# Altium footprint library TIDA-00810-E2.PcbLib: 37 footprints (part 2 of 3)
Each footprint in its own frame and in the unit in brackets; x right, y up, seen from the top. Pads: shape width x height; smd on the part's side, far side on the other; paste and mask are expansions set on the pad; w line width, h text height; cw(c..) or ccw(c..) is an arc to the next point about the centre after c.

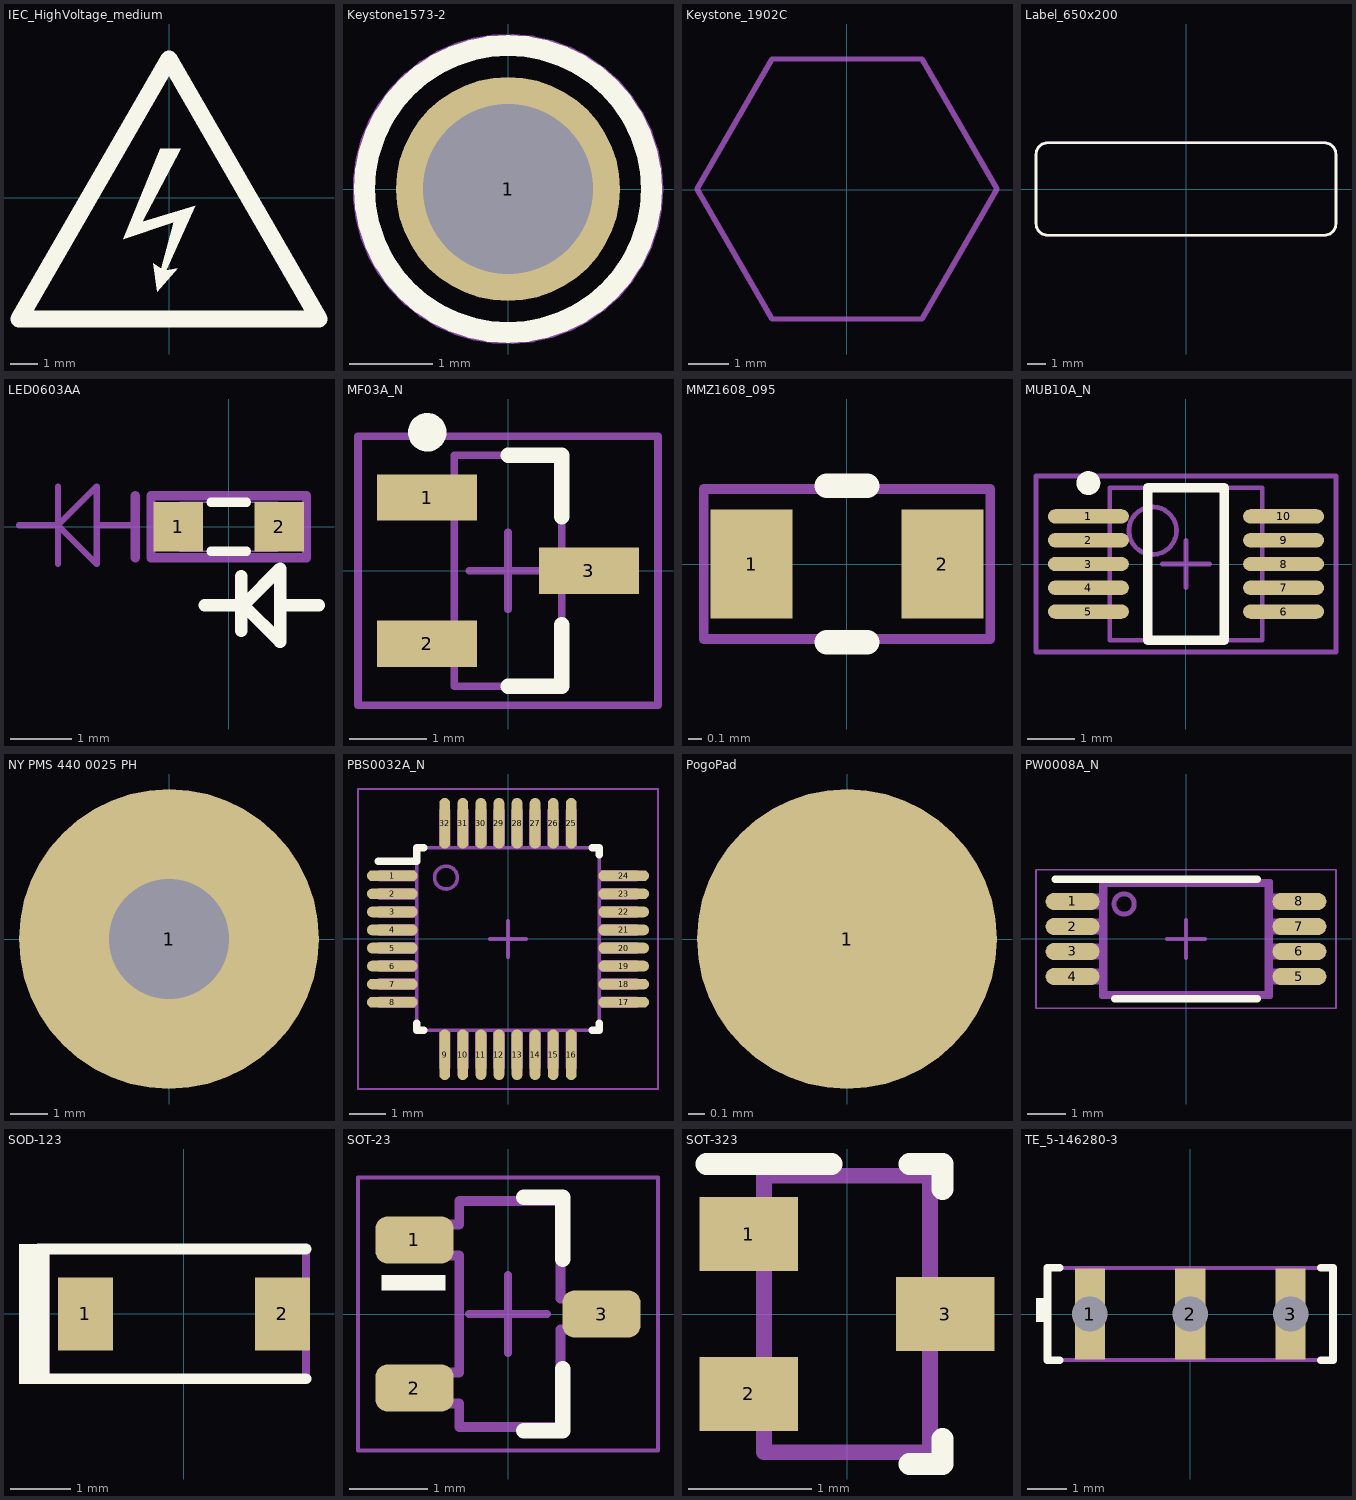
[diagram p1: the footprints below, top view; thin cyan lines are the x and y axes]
## IEC_HighVoltage_medium [mm]
Top Overlay:
  region: -0.33,1.803 0.432,1.803 -0.991,-0.889 0.965,-0.305 -0.102,-2.667 0.33,-2.591 -0.432,-3.454 -0.584,-2.413 -0.279,-2.616 0.178,-0.914 -1.676,-1.524
  lines w0.635: -5.512,-4.458 0,5.089 5.512,-4.458 -5.512,-4.458

## Keystone1573-2 [mm] "Double Turret"
height 4.7
pads (1):
  round 2.7 hole 2.05: 1(0,0)
Top Overlay:
  circle w0.254: c0,0 r1.727
Mechanical 5:
  circle w0.127: c0,0 r1.805
  text ".Designator" at -1.397,-0.381 h0.76
3D body "Keystone1573-2.stp": height 4.72, standoff -2.06, extent -1.18,-1.178 1.171,1.178

## Keystone_1902C [mil] "Hex Standoff, 4-40 threaded, nylon"
height 500
pads (1):
  round 1 on Mech3: 0(0,0)
Mechanical 5:
  lines w5: -145.29,0.49 -72.56,126.47 72.92,126.47 145.65,0.49 72.92,-125.49 -72.56,-125.49 -145.29,0.49
  text ".Designator" at -60,-20 h25
3D body "Keystone_1902C.stp": height 501, standoff 1, extent -144.95,-125.98 146,125.98

## Label_650x200 [mil] "Thermal Transfer Label"
height 1
pads (1):
  round 1 on Mech13: 0(0,0)
Top Overlay:
  lines w6: -325,-75 ccw(c-300,-75) -300,-100 300,-100 ccw(c300,-75) 325,-75 325,75 ccw(c300,75) 300,100 -300,100 ccw(c-300,75) -325,75 -325,-75
Mechanical 5:
  lines w5: -325,-75 ccw(c-300,-75) -300,-100 300,-100 ccw(c300,-75) 325,-75 325,75 ccw(c300,75) 300,100 -300,100 ccw(c-300,75) -325,75 -325,-75
  text ".Designator" at -60,-20 h25
3D body: height 1, standoff 0, extent -325.02,-100.02 325.02,100.02

## LED0603AA [mil]
height 118.11
pads (2):
  rect 32x32 smd: 1(-32.48,0) 2(32.48,0)
Top Overlay:
  lines w6: -11.42,-15.75 11.42,-15.75 ; -11.42,15.75 11.42,15.75
  lines w8: -15.58,-50.44 9.42,-50.44 33,-26.85 33,-73.81 ; 8,-66.85 8,-31.85 ; 9.62,-50.44 33,-73.81 ; 32.79,-73.81 33,-73.81 ; 33,-50.33 58,-50.33
Mechanical 5:
  lines w6: -60,-20 -60,20 ; -50,-20 -50,20 50,20 50,-20 -50,-20
  text ".designator" at -140,-10 h25
Mechanical 15:
  lines w1: -31.5,-15.75 -31.5,15.75 31.5,15.75 31.5,-15.75 -31.5,-15.75
  lines w3.94: -134.79,0.96 -109.79,0.96 ; -109.79,-24.04 -109.79,25.96 ; -84.79,0.96 -59.79,0.96 ; -109.79,0.96 -84.79,-24.04 -84.79,25.96 -109.79,0.96

## MF03A_N [mm] "SOT23, 3-Leads, Body 2.9x1.3mm, Pitch 0.95mm, Lead Span 2.4mm, IPC Medium Density"
height 1.12
pads (3):
  rect 1.3x0.6 smd: 1(-1.05,0.95) 2(-1.05,-0.95) 3(1.05,0)
Top Overlay:
  circle w0.25: c-1.05,1.8 r0.125
  lines w0.2: 0,-1.5 0.7,-1.5 0.7,-0.7 ; 0,1.5 0.7,1.5 0.7,0.7
Mechanical 5:
  text ".Designator" at -0.254,-0.762 h0.64
Mechanical 13:
  lines w0.1: -0.7,-1.5 0.7,-1.5 0.7,1.5 -0.7,1.5 -0.7,-1.5
Mechanical 15:
  lines w0.1: -0.5,0 0.5,0 ; 0,-0.5 0,0.5 ; -1.95,-1.75 1.95,-1.75 1.95,1.75 -1.95,1.75 -1.95,-1.75
3D body: height 1.12, standoff 0, extent -0.7,-1.5 0.7,1.5

## MMZ1608_095 [mm] "TDK"
height 0.95
pads (2):
  rect 0.6x0.8 smd: 1(-0.7,0) 2(0.7,0)
Top Overlay:
  lines w0.18: -0.15,-0.575 0.15,-0.575 ; -0.15,0.575 0.15,0.575
Mechanical 5:
  lines w0.07: -1.05,-0.55 -1.05,0.55 1.05,0.55 1.05,-0.55 -1.05,-0.55
  text ".Designator" at -0.508,-0.356 h0.64
3D body: height 0.95, standoff 0, extent -0.874,-0.474 -0.501,0.474
3D body: height 0.95, standoff 0, extent -0.499,-0.474 0.499,0.474
3D body: height 0.95, standoff 0, extent 0.501,-0.474 0.874,0.474

## MUB10A_N [mm] "TSSOP, 10-Leads, Body 3x3mm, Pitch 0.5mm, IPC Medium Density"
height 1.09
pads (10):
  oval 1.7x0.3 smd: 1(-2.05,1) 2(-2.05,0.5) 3(-2.05,0) 4(-2.05,-0.5) 5(-2.05,-1) 6(2.05,-1) 7(2.05,-0.5) 8(2.05,0) 9(2.05,0.5) 10(2.05,1)
Top Overlay:
  circle w0.25: c-2.05,1.7 r0.125
  lines w0.2: -0.8,-1.6 0.8,-1.6 0.8,1.6 -0.8,1.6 -0.8,-1.6
Mechanical 5:
  text ".Designator" at -0.379,0.508 h0.64
Mechanical 13:
  circle w0.1: c-0.7,0.7 r0.5
  lines w0.1: -1.6,-1.6 1.6,-1.6 1.6,1.6 -1.6,1.6 -1.6,-1.6
Mechanical 15:
  lines w0.1: -0.5,0 0.5,0 ; 0,-0.5 0,0.5 ; -3.15,-1.85 3.15,-1.85 3.15,1.85 -3.15,1.85 -3.15,-1.85
3D body: height 1.09, standoff 0, extent -1.6,-1.6 1.6,1.6

## NY PMS 440 0025 PH [mm] "4-40 nylon screw and mounting hole"
height 1.905
pads (1):
  round 8 hole 3.2: 1(0,0)
Mechanical 5:
  circle w0.127: c0,0 r3.789
  text ".Designator" at -0.446,-0.131 h0.64
3D body "B_F_NY PMS 440 0025 PH.stp": height 2.69, standoff -8.74, extent -3.302,-3.3 3.296,3.3

## PBS0032A_N [mm]
height 1.2
pads (32):
  oval 1.4x0.3 smd: 1(-3.2,1.75) 2(-3.2,1.25) 3(-3.2,0.75) 4(-3.2,0.25) 5(-3.2,-0.25) 6(-3.2,-0.75) 7(-3.2,-1.25) 8(-3.2,-1.75) 17(3.2,-1.75) 18(3.2,-1.25) 19(3.2,-0.75) 20(3.2,-0.25) 21(3.2,0.25) 22(3.2,0.75) 23(3.2,1.25) 24(3.2,1.75)
  oval 0.3x1.4 smd: 9(-1.75,-3.2) 10(-1.25,-3.2) 11(-0.75,-3.2) 12(-0.25,-3.2) 13(0.25,-3.2) 14(0.75,-3.2) 15(1.25,-3.2) 16(1.75,-3.2) 25(1.75,3.2) 26(1.25,3.2) 27(0.75,3.2) 28(0.25,3.2) 29(-0.25,3.2) 30(-0.75,3.2) 31(-1.25,3.2) 32(-1.75,3.2)
Top Overlay:
  lines w0.2: -3.6,2.15 -2.527,2.15 -2.527,2.527 -2.327,2.527 ; -2.527,-2.327 -2.527,-2.527 -2.327,-2.527 ; 2.327,-2.527 2.527,-2.527 2.527,-2.327 ; 2.327,2.527 2.527,2.527 2.527,2.327
Mechanical 5:
  circle w0.1: c-1.716,1.7 r0.316
  lines w0.1: -3.556,-1.864 -2.527,-1.864 -2.527,-1.636 -3.556,-1.636 -3.556,-1.864 ; -3.556,-1.364 -2.527,-1.364 -2.527,-1.136 -3.556,-1.136 -3.556,-1.364 ; -3.556,-0.864 -2.527,-0.864 -2.527,-0.636 -3.556,-0.636 -3.556,-0.864 ; -3.556,-0.364 -2.527,-0.364 -2.527,-0.136 -3.556,-0.136 -3.556,-0.364 ; -3.556,0.136 -2.527,0.136 -2.527,0.364 -3.556,0.364 -3.556,0.136 ; -3.556,0.636 -2.527,0.636 -2.527,0.864 -3.556,0.864 -3.556,0.636 ; -3.556,1.136 -2.527,1.136 -2.527,1.364 -3.556,1.364 -3.556,1.136 ; -3.556,1.636 -2.527,1.636 -2.527,1.864 -3.556,1.864 -3.556,1.636 ; -2.527,-2.527 -2.527,2.527 2.527,2.527 2.527,-2.527 -2.527,-2.527 ; -1.864,-3.556 -1.636,-3.556 -1.636,-2.527 -1.864,-2.527 -1.864,-3.556 ; -1.864,2.527 -1.864,3.556 -1.636,3.556 -1.636,2.527 -1.864,2.527 ; -1.364,-3.556 -1.136,-3.556 -1.136,-2.527 -1.364,-2.527 -1.364,-3.556 ; -1.364,2.527 -1.364,3.556 -1.136,3.556 -1.136,2.527 -1.364,2.527 ; -0.864,-3.556 -0.636,-3.556 -0.636,-2.527 -0.864,-2.527 -0.864,-3.556 ; -0.864,2.527 -0.864,3.556 -0.636,3.556 -0.636,2.527 -0.864,2.527 ; -0.364,-3.556 -0.136,-3.556 -0.136,-2.527 -0.364,-2.527 -0.364,-3.556 ; -0.364,2.527 -0.364,3.556 -0.136,3.556 -0.136,2.527 -0.364,2.527 ; 0.136,-3.556 0.364,-3.556 0.364,-2.527 0.136,-2.527 0.136,-3.556 ; 0.136,2.527 0.136,3.556 0.364,3.556 0.364,2.527 0.136,2.527 ; 0.636,-3.556 0.864,-3.556 0.864,-2.527 0.636,-2.527 0.636,-3.556 ; 0.636,2.527 0.636,3.556 0.864,3.556 0.864,2.527 0.636,2.527 ; 1.136,-3.556 1.364,-3.556 1.364,-2.527 1.136,-2.527 1.136,-3.556 ; 1.136,2.527 1.136,3.556 1.364,3.556 1.364,2.527 1.136,2.527 ; 1.636,-3.556 1.864,-3.556 1.864,-2.527 1.636,-2.527 1.636,-3.556 ; 1.636,2.527 1.636,3.556 1.864,3.556 1.864,2.527 1.636,2.527 ; 2.527,-1.864 3.556,-1.864 3.556,-1.636 2.527,-1.636 2.527,-1.864 ; 2.527,-1.364 3.556,-1.364 3.556,-1.136 2.527,-1.136 2.527,-1.364 ; 2.527,-0.864 3.556,-0.864 3.556,-0.636 2.527,-0.636 2.527,-0.864 ; 2.527,-0.364 3.556,-0.364 3.556,-0.136 2.527,-0.136 2.527,-0.364 ; 2.527,0.136 3.556,0.136 3.556,0.364 2.527,0.364 2.527,0.136 ; 2.527,0.636 3.556,0.636 3.556,0.864 2.527,0.864 2.527,0.636 ; 2.527,1.136 3.556,1.136 3.556,1.364 2.527,1.364 2.527,1.136 ; 2.527,1.636 3.556,1.636 3.556,1.864 2.527,1.864 2.527,1.636
  text ".Designator" at 0.364,-0.51 h0.64
Mechanical 15:
  lines w0.05: -4.15,-4.15 -4.15,4.15 4.15,4.15 4.15,-4.15 -4.15,-4.15
  lines w0.1: -0.5,0 0.5,0 ; 0,-0.5 0,0.5
3D body "PBS0032A.stp": height 1.2, standoff 0, extent -3.505,-3.505 3.506,3.506

## PogoPad [mil] "No Solder Paste"
pads (1):
  round 70 smd paste-35: 1(0,0)

## PW0008A_N [mm] "TSOP, 8-Leads, Body 3x4.4mm, Pitch 0.65mm, IPC Medium Density"
height 1.2
pads (8):
  oval 1.4x0.45 smd: 1(-2.95,0.975) 2(-2.95,0.325) 3(-2.95,-0.325) 4(-2.95,-0.975) 5(2.95,-0.975) 6(2.95,-0.325) 7(2.95,0.325) 8(2.95,0.975)
Top Overlay:
  lines w0.2: -3.4,1.55 1.85,1.55 ; -1.85,-1.55 1.85,-1.55
Mechanical 5:
  lines w0.127: -2.2,-1.5 -2.2,-1.125 ; -2.2,-1.5 2.2,-1.5 ; -2.2,-1.5 -2.11,-1.41 ; -2.2,-1.125 -2.4,-1.125 -2.669,-1.125 -2.785,-1.125 -2.856,-1.125 -3.228,-1.125 -3.228,-0.825 -2.856,-0.825 -2.785,-0.825 -2.669,-0.825 -2.4,-0.825 -2.2,-0.825 ; -2.2,-1.125 -2.2,-0.825 ; -2.2,-0.825 -2.2,-0.475 ; -2.2,-0.475 -2.2,-0.175 ; -2.2,-0.475 -2.4,-0.475 -2.669,-0.475 -2.785,-0.475 -2.856,-0.475 -3.228,-0.475 -3.228,-0.175 -2.856,-0.175 -2.785,-0.175 -2.669,-0.175 -2.4,-0.175 -2.2,-0.175 ; -2.2,-0.175 -2.2,0.175 ; -2.2,0.175 -2.4,0.175 -2.669,0.175 -2.785,0.175 -2.856,0.175 -3.228,0.175 -3.228,0.475 -2.856,0.475 -2.785,0.475 -2.669,0.475 -2.4,0.475 -2.2,0.475 ; -2.2,0.175 -2.2,0.475 ; -2.2,0.475 -2.2,0.825 ; -2.2,0.825 -2.2,1.125 ; -2.2,0.825 -2.4,0.825 -2.669,0.825 -2.785,0.825 -2.856,0.825 -3.228,0.825 -3.228,1.125 -2.856,1.125 -2.785,1.125 -2.669,1.125 -2.4,1.125 -2.2,1.125 ; -2.2,1.125 -2.2,1.5 ; -2.2,1.5 2.2,1.5 ; -2.2,1.5 -2.11,1.41 ; -2.11,-1.41 2.11,-1.41 ; -2.11,-1.41 -2.11,1.41 ; -2.11,1.41 2.11,1.41 ; 2.11,-1.41 2.2,-1.5 ; 2.11,-1.41 2.11,1.41 ; 2.11,1.41 2.2,1.5 ; 2.2,-1.5 2.2,-1.125 ; 2.2,-1.125 2.4,-1.125 2.669,-1.125 2.785,-1.125 2.856,-1.125 3.228,-1.125 3.228,-0.825 2.856,-0.825 2.785,-0.825 2.669,-0.825 2.4,-0.825 2.2,-0.825 ; 2.2,-1.125 2.2,-0.825 ; 2.2,-0.825 2.2,-0.475 ; 2.2,-0.475 2.4,-0.475 2.669,-0.475 2.785,-0.475 2.856,-0.475 3.228,-0.475 3.228,-0.175 2.856,-0.175 2.785,-0.175 2.669,-0.175 2.4,-0.175 2.2,-0.175 ; 2.2,-0.475 2.2,-0.175 ; 2.2,-0.175 2.2,0.175 ; 2.2,0.175 2.2,0.475 ; 2.2,0.175 2.4,0.175 2.669,0.175 2.785,0.175 2.856,0.175 3.228,0.175 3.228,0.475 2.856,0.475 2.785,0.475 2.669,0.475 2.4,0.475 2.2,0.475 ; 2.2,0.475 2.2,0.825 ; 2.2,0.825 2.2,1.125 ; 2.2,0.825 2.4,0.825 2.669,0.825 2.785,0.825 2.856,0.825 3.228,0.825 3.228,1.125 2.856,1.125 2.785,1.125 2.669,1.125 2.4,1.125 2.2,1.125 ; 2.2,1.125 2.2,1.5 ; -1.61,0.646 ccw(c-1.61,0.91) -1.61,1.173 ccw(c-1.61,0.91) -1.61,0.646
  text ".Designator" at 0.635,0.254 h0.64
Mechanical 15:
  lines w0.05: -3.9,-1.8 3.9,-1.8 3.9,1.8 -3.9,1.8 -3.9,-1.8
  lines w0.1: -0.5,0 0.5,0 ; 0,-0.5 0,0.5
3D body "PW0008A.stp": height 1.2, standoff 0, extent -3.208,-1.5 3.208,1.5

## SOD-123 [mm] "On Semi recommended land pattern"
height 1.35
pads (2):
  rect 0.915x1.22 smd: 1(-1.637,0) 2(1.637,0)
Top Overlay:
  rectangle: -2.743,-1.169 -2.235,1.168
  lines w0.178: -2.413,-1.079 2.032,-1.079 ; -2.413,1.079 2.032,1.079
Mechanical 5:
  rectangle: -2.743,-1.169 -2.235,1.168
  lines w0.127: -2.413,-1.079 2.032,-1.079 2.032,1.079 -2.413,1.079
  text ".Designator" at 0.381,0.381 h0.64
3D body "SOD-123.stp": height 1.35, standoff 0, extent -1.932,-0.9 1.932,0.9

## SOT-23 [mm] "SOT23, 3-Leads, Body 2.9x1.3mm, Pitch 0.95mm, Lead Span 2.5mm, IPC Medium Density"
height 1.1
pads (3):
  rrect50% 1x0.6 smd: 1(-1.2,0.95) 2(-1.2,-0.95) 3(1.2,0)
Top Overlay:
  rectangle: -1.625,0.3 -0.8,0.5
  lines w0.2: 0.2,-1.5 0.7,-1.5 0.7,-0.7 ; 0.2,1.5 0.7,1.5 0.7,0.7
Mechanical 5:
  lines w0.127: -1.16,-1.15 -1.16,-0.75 -0.625,-0.75 -0.625,0.75 -1.16,0.75 -1.16,1.15 -0.625,1.15 -0.625,1.45 0.675,1.45 0.675,0.2 1.21,0.2 1.21,-0.2 0.675,-0.2 0.675,-1.45 -0.625,-1.45 -0.625,-1.15 -1.16,-1.15
  text ".Designator" at 0.305,-0.762 h0.64
Mechanical 15:
  lines w0.05: -1.925,-1.75 1.925,-1.75 1.925,1.75 -1.925,1.75 -1.925,-1.75
  lines w0.1: -0.5,0 0.5,0 ; 0,-0.5 0,0.5
3D body "SW3dPS-sot-3p290x130ll237h100.STEP": height 1, standoff 0, extent -1.16,-1.45 1.21,1.45

## SOT-323 [mm] "Zetex recommended land pattern.  March 2007"
height 1.1
pads (3):
  rect 0.8x0.6 smd: 1(-0.8,0.65) 2(-0.8,-0.65) 3(0.8,0)
Top Overlay:
  lines w0.178: -1.143,1.219 -0.127,1.219 ; 0.508,-1.219 0.775,-1.219 0.775,-1.016 ; 0.508,1.219 0.775,1.219 0.775,1.016
Mechanical 5:
  lines w0.127: -1.125,-0.8 -1.125,-0.5 -0.975,-0.5 -0.935,-0.5 -0.884,-0.5 -0.725,-0.5 -0.675,-0.5 -0.675,-0.8 -0.725,-0.8 -0.884,-0.8 -0.935,-0.8 -0.975,-0.8 -1.125,-0.8 ; -1.125,0.5 -1.125,0.8 -0.975,0.8 -0.935,0.8 -0.884,0.8 -0.725,0.8 -0.675,0.8 -0.675,0.5 -0.725,0.5 -0.884,0.5 -0.935,0.5 -0.975,0.5 -1.125,0.5 ; -0.675,-1.125 -0.675,1.125 0.675,1.125 0.675,-1.125 -0.675,-1.125 ; 0.675,-0.15 0.725,-0.15 0.884,-0.15 0.935,-0.15 0.975,-0.15 1.125,-0.15 1.125,0.15 0.975,0.15 0.935,0.15 0.884,0.15 0.725,0.15 0.675,0.15 0.675,-0.15
  text ".Designator" at 0.254,-0.508 h0.64
3D body "SC-70.stp": height 1.13, standoff 0.02, extent -1.125,-1.125 1.125,1.125

## TE_5-146280-3 [mm] "Header, 2.54mm, 3x1, TH"
height 8.72
pads (3):
  rect 0.76x2.29 hole 0.89: 1(-2.54,0) 2(0,0) 3(2.54,0)
Top Overlay:
  rectangle: -3.9,-0.2 -3.6,0.4
  lines w0.2: -3.3,-1.168 -3.607,-1.168 -3.607,1.169 -3.3,1.169 ; 3.3,-1.168 3.607,-1.168 3.607,1.169 3.3,1.169
Mechanical 5:
  lines w0.1: -3.607,-1.168 -3.607,1.169 3.607,1.169 3.607,-1.168 -3.607,-1.168 ; -2.851,-0.311 -2.851,0.311 -2.229,0.311 -2.229,-0.311 -2.851,-0.311
  text ".Designator" at -0.762,-0.254 h0.64
3D body "c-5-146280-3-g-3d.stp": height 8.13, standoff -3.05, extent -3.607,-1.168 3.607,1.169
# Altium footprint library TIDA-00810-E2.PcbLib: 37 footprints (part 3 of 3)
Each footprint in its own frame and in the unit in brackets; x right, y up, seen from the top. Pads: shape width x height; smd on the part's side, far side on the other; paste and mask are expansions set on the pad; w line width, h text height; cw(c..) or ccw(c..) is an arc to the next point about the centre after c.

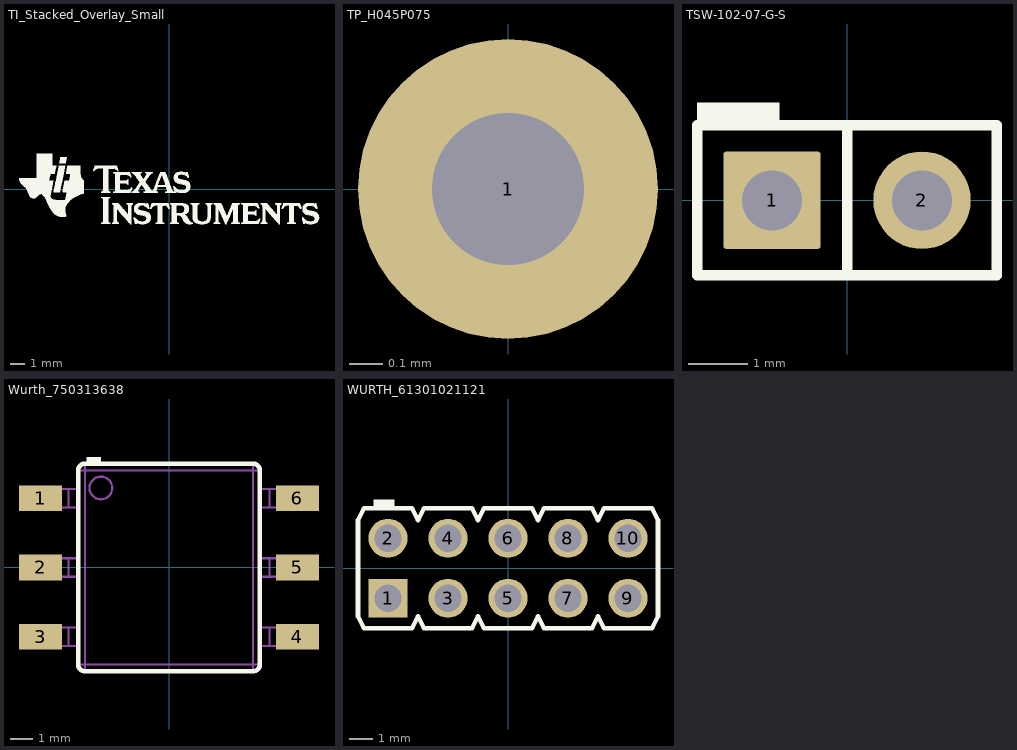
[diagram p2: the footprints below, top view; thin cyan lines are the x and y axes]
## TI_Stacked_Overlay_Small [mm]
Top Overlay:
  drawing of 18 lines, arcs and shapes, not listed

## TP_H045P075 [mil] "TP_H0.45P0.75"
height 104.33
pads (1):
  round 35 hole 17.72: 1(0,0)

## TSW-102-07-G-S [mm] "Samtec 100mil, 1x2, 230 mil above insulator"
height 8.382
pads (2):
  rrect6% 1.65x1.65 hole 1.016: 1(-1.27,0)
  round 1.65 hole 1.016: 2(1.27,0)
Top Overlay:
  rectangle: -2.54,1.27 -1.143,1.651
  lines w0.178: 0,-1.27 0,1.27 ; -2.54,-1.27 2.54,-1.27 2.54,1.27 -2.54,1.27 -2.54,-1.27
Mechanical 5:
  lines w0.127: -2.54,-1.27 -2.54,1.27 2.54,1.27 2.54,-1.27 -2.54,-1.27
  text ".Designator" at 0.762,0.254 h0.64
3D body "SamtecTSW-07_2x1.stp": height 8.38, standoff -2.54, extent -2.54,-1.27 2.54,1.27

## Wurth_750313638 [mm] "SMD, 6-Leads, Body 8x9.14mm, Pitch 3.05mm"
height 7.62
pads (6):
  rect 1.9x1.14 smd: 1(-5.655,3.05) 2(-5.655,0) 3(-5.655,-3.05) 4(5.655,-3.05) 5(5.655,0) 6(5.655,3.05)
Top Overlay:
  rectangle: -3.625,4.57 -3,4.875
  lines w0.2: -4,-4.27 ccw(c-3.7,-4.27) -3.7,-4.57 3.7,-4.57 ccw(c3.7,-4.27) 4,-4.27 4,4.27 ccw(c3.7,4.27) 3.7,4.57 -3.7,4.57 ccw(c-3.7,4.27) -4,4.27 -4,-4.27
Mechanical 5:
  circle w0.1: c-3,3.5 r0.5
  lines w0.1: -4,-3.455 -4.43,-3.455 ; -4,-2.645 -4.43,-2.645 ; -4,-0.405 -4.43,-0.405 ; -4,0.405 -4.43,0.405 ; -4,2.645 -4.43,2.645 ; -4,3.455 -4.43,3.455 ; 4,-3.455 4.43,-3.455 ; 4,-2.645 4.43,-2.645 ; 4,-0.405 4.43,-0.405 ; 4,0.405 4.43,0.405 ; 4,2.645 4.43,2.645 ; 4,3.455 4.43,3.455 ; -5.47,-3.455 -5.376,-3.455 ; -5.47,-3.455 -6.35,-3.455 -6.35,-2.645 -5.47,-2.645 ; -5.47,-3.455 -5.47,-2.645 ; -5.47,-2.645 -5.376,-2.645 ; -5.47,-0.405 -6.35,-0.405 -6.35,0.405 -5.47,0.405 ; -5.47,-0.405 -5.376,-0.405 ; -5.47,-0.405 -5.47,0.405 ; -5.47,0.405 -5.376,0.405 ; -5.47,2.645 -5.376,2.645 ; -5.47,2.645 -6.35,2.645 -6.35,3.455 -5.47,3.455 ; -5.47,2.645 -5.47,3.455 ; -5.47,3.455 -5.376,3.455 ; -5.376,-3.455 -4.9,-3.455 ; -5.376,-3.455 -5.376,-2.645 ; -5.376,-2.645 -4.9,-2.645 ; -5.376,-0.405 -4.9,-0.405 ; -5.376,-0.405 -5.376,0.405 ; -5.376,0.405 -4.9,0.405 ; -5.376,2.645 -4.9,2.645 ; -5.376,2.645 -5.376,3.455 ; -5.376,3.455 -4.9,3.455 ; -4.9,-3.455 -4.43,-3.455 ; -4.9,-3.455 -4.9,-2.645 ; -4.9,-2.645 -4.43,-2.645 ; -4.9,-0.405 -4.43,-0.405 ; -4.9,-0.405 -4.9,0.405 ; -4.9,0.405 -4.43,0.405 ; -4.9,2.645 -4.43,2.645 ; -4.9,2.645 -4.9,3.455 ; -4.9,3.455 -4.43,3.455 ; -4.43,-3.455 -4.43,-2.645 ; -4.43,-0.405 -4.43,0.405 ; -4.43,2.645 -4.43,3.455 ; -4,-4.27 ccw(c-3.7,-4.27) -3.7,-4.57 ; -4,-4.27 -4,4.27 ; -4,-4.27 -3.7,-4.27 ; -4,4.27 cw(c-3.7,4.27) -3.7,4.57 ; -4,4.27 -3.7,4.27 ; -3.7,-4.57 3.7,-4.57 ; -3.7,-4.57 -3.7,-4.27 ; -3.7,-4.27 -3.7,4.27 ; -3.7,-4.27 3.7,-4.27 ; -3.7,4.27 3.7,4.27 ; -3.7,4.27 -3.7,4.57 ; -3.7,4.57 3.7,4.57 ; 3.7,-4.57 ccw(c3.7,-4.27) 4,-4.27 ; 3.7,-4.57 3.7,-4.27 ; 3.7,-4.27 3.7,4.27 ; 3.7,-4.27 4,-4.27 ; 3.7,4.27 3.7,4.57 ; 3.7,4.27 4,4.27 ; 3.7,4.57 cw(c3.7,4.27) 4,4.27 ; 4,-4.27 4,4.27 ; 4.43,-3.455 4.9,-3.455 ; 4.43,-3.455 4.43,-2.645 ; 4.43,-2.645 4.9,-2.645 ; 4.43,-0.405 4.9,-0.405 ; 4.43,-0.405 4.43,0.405 ; 4.43,0.405 4.9,0.405 ; 4.43,2.645 4.9,2.645 ; 4.43,2.645 4.43,3.455 ; 4.43,3.455 4.9,3.455 ; 4.9,-3.455 5.376,-3.455 ; 4.9,-3.455 4.9,-2.645 ; 4.9,-2.645 5.376,-2.645 ; 4.9,-0.405 5.376,-0.405 ; 4.9,-0.405 4.9,0.405 ; 4.9,0.405 5.376,0.405 ; 4.9,2.645 5.376,2.645 ; 4.9,2.645 4.9,3.455 ; 4.9,3.455 5.376,3.455 ; 5.376,-3.455 5.47,-3.455 ; 5.376,-3.455 5.376,-2.645 ; 5.376,-2.645 5.47,-2.645 ; 5.376,-0.405 5.47,-0.405 ; 5.376,-0.405 5.376,0.405 ; 5.376,0.405 5.47,0.405 ; 5.376,2.645 5.47,2.645 ; 5.376,2.645 5.376,3.455 ; 5.376,3.455 5.47,3.455 ; 5.47,-3.455 6.35,-3.455 6.35,-2.645 5.47,-2.645 ; 5.47,-3.455 5.47,-2.645 ; 5.47,-0.405 6.35,-0.405 6.35,0.405 5.47,0.405 ; 5.47,-0.405 5.47,0.405 ; 5.47,2.645 6.35,2.645 6.35,3.455 5.47,3.455 ; 5.47,2.645 5.47,3.455
  text ".Designator" at 6.858,0.508 h0.64
3D body "750313638.stp": height 7.62, standoff 0, extent -6.35,-4.57 6.35,4.57

## WURTH_61301021121 [mm] "Header, 2.54mm, 5x2, TH"
height 8.89
pads (10):
  rect 1.65x1.65 hole 1.15: 1(-5.08,-1.27)
  round 1.65 hole 1.15: 2(-5.08,1.27) 3(-2.54,-1.27) 4(-2.54,1.27) 5(0,-1.27) 6(0,1.27) 7(2.54,-1.27) 8(2.54,1.27) 9(5.08,-1.27) 10(5.08,1.27)
Top Overlay:
  rectangle: -5.7,2.6 -4.8,2.9
  lines w0.2: -6.35,-2.04 -6.35,2.04 -6.1,2.54 -4.06,2.54 -3.81,2.04 -3.56,2.54 -1.52,2.54 -1.27,2.04 -1.02,2.54 1.02,2.54 1.27,2.04 1.52,2.54 3.56,2.54 3.81,2.04 4.06,2.54 6.1,2.54 6.35,2.04 6.35,-2.04 6.1,-2.54 4.06,-2.54 3.81,-2.04 3.56,-2.54 1.52,-2.54 1.27,-2.04 1.02,-2.54 -1.02,-2.54 -1.27,-2.04 -1.52,-2.54 -3.56,-2.54 -3.81,-2.04 -4.06,-2.54 -6.1,-2.54 -6.35,-2.04
Mechanical 5:
  lines w0.1: -6.35,-2.04 -6.1,-2.54 -4.06,-2.54 -3.81,-2.04 -3.56,-2.54 -1.52,-2.54 -1.27,-2.04 -1.02,-2.54 1.02,-2.54 1.27,-2.04 1.52,-2.54 3.56,-2.54 3.81,-2.04 4.06,-2.54 6.1,-2.54 6.35,-2.04 6.35,2.04 6.1,2.54 4.06,2.54 3.81,2.04 3.56,2.54 1.52,2.54 1.27,2.04 1.02,2.54 -1.02,2.54 -1.27,2.04 -1.52,2.54 -3.56,2.54 -3.81,2.04 -4.06,2.54 -6.1,2.54 -6.35,2.04 -6.35,-2.04
  text ".Designator" at -0.508,-0.381 h0.64
3D body "61301021121.stp": height 8.54, standoff -3, extent -6.35,-2.54 6.35,2.54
